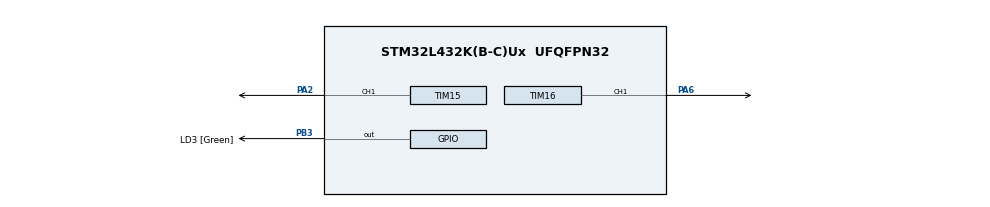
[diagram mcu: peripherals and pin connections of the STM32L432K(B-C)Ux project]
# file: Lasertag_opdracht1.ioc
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Mcu.Family=STM32L4
Mcu.Name=STM32L432K(B-C)Ux
Mcu.Package=UFQFPN32
NVIC.PriorityGroup=NVIC_PRIORITYGROUP_4
NVIC.TIM1_BRK_TIM15_IRQn=true\:0\:0\:false\:false\:true\:true\:true\:true
PA0.GPIO_Label=MCO [High speed clock in]
PA0.Signal=RCC_CK_IN
PA13\ (JTMS-SWDIO).GPIO_Label=SWDIO
PA13\ (JTMS-SWDIO).Mode=Serial_Wire
PA13\ (JTMS-SWDIO).Signal=SYS_JTMS-SWDIO
PA14\ (JTCK-SWCLK).GPIO_Label=SWCLK
PA14\ (JTCK-SWCLK).Mode=Serial_Wire
PA14\ (JTCK-SWCLK).Signal=SYS_JTCK-SWCLK
PA15\ (JTDI).GPIO_Label=VCP_RX
PA15\ (JTDI).Signal=USART2_RX
PA2.Signal=S_TIM15_CH1
PA6.Signal=S_TIM16_CH1
PB3\ (JTDO-TRACESWO).GPIO_Label=LD3 [Green]
PB3\ (JTDO-TRACESWO).Signal=GPIO_Output
PC14-OSC32_IN\ (PC14).Signal=RCC_OSC32_IN
PC15-OSC32_OUT\ (PC15).Signal=RCC_OSC32_OUT
ProjectManager.HeapSize=0x200
ProjectManager.StackSize=0x400
ProjectManager.TargetToolchain=MDK-ARM V5.32
RCC.AHBFreq_Value=80000000
RCC.APB1Freq_Value=80000000
RCC.APB1TimFreq_Value=80000000
RCC.APB2Freq_Value=80000000
RCC.APB2TimFreq_Value=80000000
RCC.CortexFreq_Value=80000000
RCC.HCLKFreq_Value=80000000
RCC.HSE_VALUE=8000000
RCC.HSI16_VALUE=16000000
RCC.HSI48_VALUE=48000000
RCC.HSI_VALUE=16000000
RCC.LSE_VALUE=32768
RCC.MSI_VALUE=4000000
RCC.PLLMUL=RCC_PLLMUL_4
RCC.PLLN=40
RCC.SYSCLKFreq_VALUE=80000000
RCC.SYSCLKSource=RCC_SYSCLKSOURCE_PLLCLK
RCC.VCOOutputFreq_Value=160000000
SH.S_TIM15_CH1.0=TIM15_CH1,PWM Generation1 CH1
SH.S_TIM16_CH1.0=TIM16_CH1,PWM Generation1 CH1
TIM15.Channel-PWM\ Generation1\ CH1=TIM_CHANNEL_1
TIM15.Period=889
TIM15.Prescaler=79
TIM16.Channel=TIM_CHANNEL_1
TIM16.Period=2104
TIM16.Pulse=1052
VP_TIM15_VS_ClockSourceINT.Mode=Internal
VP_TIM16_VS_ClockSourceINT.Mode=Enable_Timer
board=NUCLEO-L432KC

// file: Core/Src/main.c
/* USER CODE BEGIN Header */
/**
  ******************************************************************************
  * @file           : main.c
  * @brief          : Main program body
  ******************************************************************************
  * @attention
  *
  * Copyright (c) 2026 STMicroelectronics.
  * All rights reserved.
  *
  * This software is licensed under terms that can be found in the LICENSE file
  * in the root directory of this software component.
  * If no LICENSE file comes with this software, it is provided AS-IS.
  *
  ******************************************************************************
  */
/* USER CODE END Header */
#include "main.h"

/* USER CODE BEGIN Includes */
#include "rc5_encode.h"
#include "ir_common.h"
/* USER CODE END Includes */

/* USER CODE BEGIN PD */

#define RC5_REPEAT_INTERVAL_MS 120U

/* USER CODE END PD */

TIM_HandleTypeDef htim15;
TIM_HandleTypeDef htim16;

/* USER CODE BEGIN PV */

static uint32_t last_send_tick = 0;
static RC5_Ctrl_t rc5_toggle = RC5_CTRL_RESET;

/* USER CODE END PV */

void SystemClock_Config(void);
static void MX_GPIO_Init(void);
static void MX_TIM15_Init(void);
static void MX_TIM16_Init(void);

int main(void)
{

  /* MCU Configuration--------------------------------------------------------*/

  /* Reset of all peripherals, Initializes the Flash interface and the Systick. */
  HAL_Init();

  /* Configure the system clock */
  SystemClock_Config();

  /* Initialize all configured peripherals */
  MX_GPIO_Init();
  MX_TIM15_Init();
  MX_TIM16_Init();
  /* USER CODE BEGIN 2 */

  /* Initialize RC5 encoder */
  RC5_Encode_Init();

  /* Wait a moment before starting */
  HAL_Delay(500);

  /* USER CODE END 2 */

  /* Infinite loop */
  while (1)
  {

    /* USER CODE BEGIN 3 */

    /* Repeat transmission at a configurable rate. */
    if ((HAL_GetTick() - last_send_tick) >= RC5_REPEAT_INTERVAL_MS)
    {
      HAL_GPIO_TogglePin(LD3_GPIO_Port, LD3_Pin);

      /* Send RC5 frame: Address=0, Command=12 */
      RC5_Encode_SendFrame(0, 12, rc5_toggle);
      rc5_toggle = (rc5_toggle == RC5_CTRL_RESET) ? RC5_CTRL_SET : RC5_CTRL_RESET;

      last_send_tick = HAL_GetTick();
    }
  }
  /* USER CODE END 3 */
}

void SystemClock_Config(void)
{
  RCC_OscInitTypeDef RCC_OscInitStruct = {0};
  RCC_ClkInitTypeDef RCC_ClkInitStruct = {0};

  /** Configure the main internal regulator output voltage
  */
  if (HAL_PWREx_ControlVoltageScaling(PWR_REGULATOR_VOLTAGE_SCALE1) != HAL_OK)
  {
    Error_Handler();
  }

  /** Initializes the RCC Oscillators according to the specified parameters
  * in the RCC_OscInitTypeDef structure.
  */
  RCC_OscInitStruct.OscillatorType = RCC_OSCILLATORTYPE_MSI;
  RCC_OscInitStruct.MSIState = RCC_MSI_ON;
  RCC_OscInitStruct.MSICalibrationValue = 0;
  RCC_OscInitStruct.MSIClockRange = RCC_MSIRANGE_6;
  RCC_OscInitStruct.PLL.PLLState = RCC_PLL_ON;
  RCC_OscInitStruct.PLL.PLLSource = RCC_PLLSOURCE_MSI;
  RCC_OscInitStruct.PLL.PLLM = 1;
  RCC_OscInitStruct.PLL.PLLN = 16;
  RCC_OscInitStruct.PLL.PLLP = RCC_PLLP_DIV7;
  RCC_OscInitStruct.PLL.PLLQ = RCC_PLLQ_DIV2;
  RCC_OscInitStruct.PLL.PLLR = RCC_PLLR_DIV2;
  if (HAL_RCC_OscConfig(&RCC_OscInitStruct) != HAL_OK)
  {
    Error_Handler();
  }

  /** Initializes the CPU, AHB and APB buses clocks
  */
  RCC_ClkInitStruct.ClockType = RCC_CLOCKTYPE_HCLK|RCC_CLOCKTYPE_SYSCLK
                              |RCC_CLOCKTYPE_PCLK1|RCC_CLOCKTYPE_PCLK2;
  RCC_ClkInitStruct.SYSCLKSource = RCC_SYSCLKSOURCE_PLLCLK;
  RCC_ClkInitStruct.AHBCLKDivider = RCC_SYSCLK_DIV1;
  RCC_ClkInitStruct.APB1CLKDivider = RCC_HCLK_DIV1;
  RCC_ClkInitStruct.APB2CLKDivider = RCC_HCLK_DIV1;

  if (HAL_RCC_ClockConfig(&RCC_ClkInitStruct, FLASH_LATENCY_1) != HAL_OK)
  {
    Error_Handler();
  }
}

static void MX_TIM15_Init(void)
{

  TIM_ClockConfigTypeDef sClockSourceConfig = {0};
  TIM_MasterConfigTypeDef sMasterConfig = {0};
  TIM_OC_InitTypeDef sConfigOC = {0};
  TIM_BreakDeadTimeConfigTypeDef sBreakDeadTimeConfig = {0};

  htim15.Instance = TIM15;
  htim15.Init.Prescaler = 31;
  htim15.Init.CounterMode = TIM_COUNTERMODE_UP;
  htim15.Init.Period = 888;
  htim15.Init.ClockDivision = TIM_CLOCKDIVISION_DIV1;
  htim15.Init.RepetitionCounter = 0;
  htim15.Init.AutoReloadPreload = TIM_AUTORELOAD_PRELOAD_DISABLE;
  if (HAL_TIM_Base_Init(&htim15) != HAL_OK)
  {
    Error_Handler();
  }
  sClockSourceConfig.ClockSource = TIM_CLOCKSOURCE_INTERNAL;
  if (HAL_TIM_ConfigClockSource(&htim15, &sClockSourceConfig) != HAL_OK)
  {
    Error_Handler();
  }
  if (HAL_TIM_PWM_Init(&htim15) != HAL_OK)
  {
    Error_Handler();
  }
  sMasterConfig.MasterOutputTrigger = TIM_TRGO_RESET;
  sMasterConfig.MasterSlaveMode = TIM_MASTERSLAVEMODE_DISABLE;
  if (HAL_TIMEx_MasterConfigSynchronization(&htim15, &sMasterConfig) != HAL_OK)
  {
    Error_Handler();
  }
  sConfigOC.OCMode = TIM_OCMODE_PWM1;
  sConfigOC.Pulse = 0;
  sConfigOC.OCPolarity = TIM_OCPOLARITY_HIGH;
  sConfigOC.OCNPolarity = TIM_OCNPOLARITY_HIGH;
  sConfigOC.OCFastMode = TIM_OCFAST_DISABLE;
  sConfigOC.OCIdleState = TIM_OCIDLESTATE_RESET;
  sConfigOC.OCNIdleState = TIM_OCNIDLESTATE_RESET;
  if (HAL_TIM_PWM_ConfigChannel(&htim15, &sConfigOC, TIM_CHANNEL_1) != HAL_OK)
  {
    Error_Handler();
  }
  sBreakDeadTimeConfig.OffStateRunMode = TIM_OSSR_DISABLE;
  sBreakDeadTimeConfig.OffStateIDLEMode = TIM_OSSI_DISABLE;
  sBreakDeadTimeConfig.LockLevel = TIM_LOCKLEVEL_OFF;
  sBreakDeadTimeConfig.DeadTime = 0;
  sBreakDeadTimeConfig.BreakState = TIM_BREAK_DISABLE;
  sBreakDeadTimeConfig.BreakPolarity = TIM_BREAKPOLARITY_HIGH;
  sBreakDeadTimeConfig.AutomaticOutput = TIM_AUTOMATICOUTPUT_DISABLE;
  if (HAL_TIMEx_ConfigBreakDeadTime(&htim15, &sBreakDeadTimeConfig) != HAL_OK)
  {
    Error_Handler();
  }
  HAL_TIM_MspPostInit(&htim15);

}

static void MX_TIM16_Init(void)
{

  TIM_OC_InitTypeDef sConfigOC = {0};
  TIM_BreakDeadTimeConfigTypeDef sBreakDeadTimeConfig = {0};

  htim16.Instance = TIM16;
  htim16.Init.Prescaler = 0;
  htim16.Init.CounterMode = TIM_COUNTERMODE_UP;
  htim16.Init.Period = 842;
  htim16.Init.ClockDivision = TIM_CLOCKDIVISION_DIV1;
  htim16.Init.RepetitionCounter = 0;
  htim16.Init.AutoReloadPreload = TIM_AUTORELOAD_PRELOAD_DISABLE;
  if (HAL_TIM_Base_Init(&htim16) != HAL_OK)
  {
    Error_Handler();
  }
  if (HAL_TIM_PWM_Init(&htim16) != HAL_OK)
  {
    Error_Handler();
  }
  sConfigOC.OCMode = TIM_OCMODE_PWM1;
  sConfigOC.Pulse = 210;
  sConfigOC.OCPolarity = TIM_OCPOLARITY_HIGH;
  sConfigOC.OCNPolarity = TIM_OCNPOLARITY_HIGH;
  sConfigOC.OCFastMode = TIM_OCFAST_DISABLE;
  sConfigOC.OCIdleState = TIM_OCIDLESTATE_RESET;
  sConfigOC.OCNIdleState = TIM_OCNIDLESTATE_RESET;
  if (HAL_TIM_PWM_ConfigChannel(&htim16, &sConfigOC, TIM_CHANNEL_1) != HAL_OK)
  {
    Error_Handler();
  }
  sBreakDeadTimeConfig.OffStateRunMode = TIM_OSSR_DISABLE;
  sBreakDeadTimeConfig.OffStateIDLEMode = TIM_OSSI_DISABLE;
  sBreakDeadTimeConfig.LockLevel = TIM_LOCKLEVEL_OFF;
  sBreakDeadTimeConfig.DeadTime = 0;
  sBreakDeadTimeConfig.BreakState = TIM_BREAK_DISABLE;
  sBreakDeadTimeConfig.BreakPolarity = TIM_BREAKPOLARITY_HIGH;
  sBreakDeadTimeConfig.AutomaticOutput = TIM_AUTOMATICOUTPUT_DISABLE;
  if (HAL_TIMEx_ConfigBreakDeadTime(&htim16, &sBreakDeadTimeConfig) != HAL_OK)
  {
    Error_Handler();
  }
  HAL_TIM_MspPostInit(&htim16);

}

static void MX_GPIO_Init(void)
{
  GPIO_InitTypeDef GPIO_InitStruct = {0};

  /* GPIO Ports Clock Enable */
  __HAL_RCC_GPIOC_CLK_ENABLE();
  __HAL_RCC_GPIOA_CLK_ENABLE();
  __HAL_RCC_GPIOB_CLK_ENABLE();

  /*Configure GPIO pin Output Level */
  HAL_GPIO_WritePin(LD3_GPIO_Port, LD3_Pin, GPIO_PIN_RESET);

  /*Configure GPIO pin : VCP_RX_Pin */
  GPIO_InitStruct.Pin = VCP_RX_Pin;
  GPIO_InitStruct.Mode = GPIO_MODE_AF_PP;
  GPIO_InitStruct.Pull = GPIO_NOPULL;
  GPIO_InitStruct.Speed = GPIO_SPEED_FREQ_VERY_HIGH;
  GPIO_InitStruct.Alternate = GPIO_AF3_USART2;
  HAL_GPIO_Init(VCP_RX_GPIO_Port, &GPIO_InitStruct);

  /*Configure GPIO pin : LD3_Pin */
  GPIO_InitStruct.Pin = LD3_Pin;
  GPIO_InitStruct.Mode = GPIO_MODE_OUTPUT_PP;
  GPIO_InitStruct.Pull = GPIO_NOPULL;
  GPIO_InitStruct.Speed = GPIO_SPEED_FREQ_LOW;
  HAL_GPIO_Init(LD3_GPIO_Port, &GPIO_InitStruct);

}

void Error_Handler(void)
{
  __disable_irq();
  while (1)
  {
  }
}
